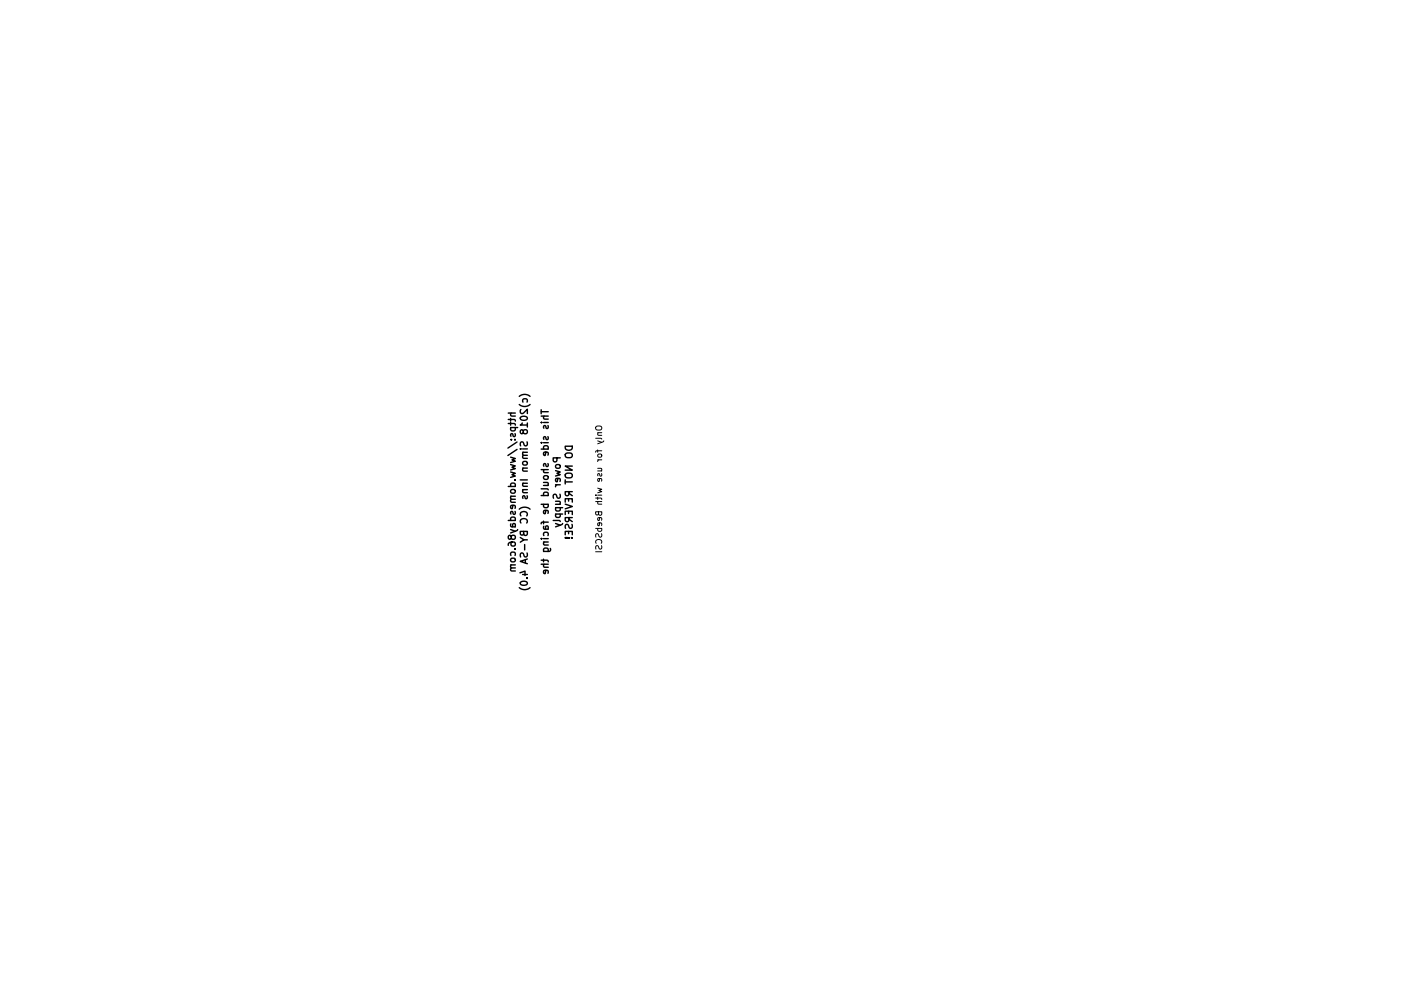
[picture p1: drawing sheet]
<svg xmlns="http://www.w3.org/2000/svg" width="297mm" height="210mm" viewBox="0 0 297 210" stroke-linecap="round" stroke-linejoin="round" font-family="sans-serif">
<g fill="none" stroke="#000" stroke-width=".21">
<path d="M126.3 93h1.1l.2 .2M126.5 90.4h.7a.43 .43 0 0 1 .4 .4 .43 .43 0 0 1-.4 .4h-.5a.44 .44 0 0 1-.4-.3 .44 .44 0 0 1 .2-.5zM126.7 99.4h.8v.5M126.7 91.8h.9M126.7 93.5l.9 .3M126.7 95.5v.5M126.7 97.6h.9M126.7 99.9h.9M126.8 96.4l.5-.1 .3 .5-.3 .2h-.3l-.3-.2zM126.8 91.8v.5l.8 .1M127 97.6l-.3 .3M127.6 95.6h-1.1l-.2 .4"/>
<path d="M128 93.5l-.1 .2-1.2 .5M126.3 105.1h.1M126.3 105.7h1.1l.2 .3M126.3 106.4h1.3M126.3 112.1h1.3M126.3 117.1h1.3M126.4 115.3a.58 .58 0 0 1 .5-.8 .58 .58 0 0 1 .6 .8M126.7 103.6l.9 .2-.6 .3 .6 .2-.9 .3M126.7 105.5v.5M126.7 105.1h.9M126.8 112.1l-.1 .4 .3 .2 .5-.1v-.5M126.8 106.4v.5l.8 .1"/>
<path d="M126.9 108.6l-.1 .5-.4 .1-.1-.6h1.3v.5l-.4 .2-.3-.3M127.2 101.5l-.2 .6h-.2l-.1-.4 .2-.2 .6 .1v.5M127.2 109.8l-.2 .6h-.2l-.1-.4 .2-.2 .6 .1v.5M127.2 110.9l-.2 .7-.2-.1-.1-.4 .2-.2 .6 .1v.5M127.5 100.5v.5h-.3l-.2-.5-.3 .2 .1 .3M127.5 113.2l.1 .5-.1 .2h-.4l-.3-.6-.3-.1-.2 .3 .1 .5M127.5 115.8l.1 .5-.3 .2-.3-.1-.2-.6h-.4l-.1 .2 .1 .5"/>
</g>
<g fill="none" stroke="#000" stroke-width=".3">
<path d="M107.8 89h1.2l.3 .4M107.8 89.9h1.2l.3 .3M107.8 87.6h1.5M108.3 97l1 .3-.8 .3 .8 .3-1 .2M108.3 98.6l1 .3-.8 .2 .8 .3-1 .3M108.3 88.8v.6M108.3 89.6v.6M108.3 90.7h1.5M108.3 90.7v.4l.2 .3 .7-.1v-.6M108.3 93.3h.2M108.4 87.6l-.1 .3v.3l1 .1M109.1 93.3h.2"/>
<path d="M109.2 92v.6h-.4l-.3-.6-.2 .2v.4M109.6 93.8l-1.9 1.3M109.6 95.4l-1.9 1.2M110.1 84.1a1.72 1.72 0 0 1 2.3 0M110.1 85.8a1.72 1.72 0 0 0 2.3 0M110.3 95.2h.2M110.4 88.5a.89 .89 0 0 1 1.4 .3 .85 .85 0 0 1-1.5-.1zM110.5 86.9l-.2 .6 .4 .2 1.1-.9v.9M110.7 89.7l-.4 .5h1.5M110.8 95.2h1M110.8 96h1M110.8 99.3h1"/>
<path d="M110.9 85.3l-.1-.4 .3-.3 .6 .1v.6M110.9 98l.6-.1 .2 .1 .1 .4-.3 .3h-.4l-.3-.3zM111 91.5l-.3-.3h-.2l-.2 .3 .1 .4 .4 .1 .2-.7 .2-.1h.5l.1 .3v.2l-.3 .3h-.4l-.1-.3M111 96l-.2 .2 .1 .3 .9 .1M111 99.3l-.2 .2 .1 .4 .9 .1M111 96.6l-.2 .2 .1 .4h.9M111.7 93.7l.1 .6-.3 .3-.3-.1-.3-.7h-.4l-.2 .2 .1 .6M111.8 89.7v.9M114.7 89.6h.2M114.7 93.9h.2M114.7 86.9v.9M114.7 87.4h1.5"/>
<path d="M114.7 88.3h1.5M114.7 95.3h1.5M114.7 99.6h1.5M115.2 89.6h1M115.2 93.9h1M115.3 95.3l-.1-.4 .3-.3 .7 .1v.6M115.4 88.3l-.2 .2 .1 .4h.9M115.4 99.6l-.2 .3 .1 .3 .9 .1M115.7 95.9l-.1 .7h-.3l-.1-.5 .3-.2 .7 .1v.6M116.2 90.3v.6h-.4l-.3-.6-.3 .2 .1 .4M116.2 92.6v.6h-.4l-.3-.6-.3 .3 .1 .3M116.2 98.4v.5h-.4l-.3-.5-.3 .2 .1 .3"/>
<path d="M117.8 99.9l1 .2-.7 .3 .7 .3-1 .3M117.9 98.6h.7l.2 .3-.1 .3-.2 .2-.6-.1-.1-.2zM118.1 97.1l-.1 .8-.2 .1-.4-.1-.1-.8h1.5M119.8 94.7h1.5a.76 .76 0 0 1-.7 .8 .76 .76 0 0 1-.8-.8zM120.1 96.2a1.01 1.01 0 0 1 1.2 .3 .5 .5 0 0 1-.5 .6h-.5a.5 .5 0 0 1-.5-.4 .5 .5 0 0 1 .3-.5zM121.3 98.9h-1.5l1.5 .8h-1.5M107.8 103.2h1.5M107.8 110.4h1.5M108.3 100.1l1 .3-.8 .3 .8 .3-1 .3M108.3 105.3h1M108.3 112.4l1 .3M108.3 119.9h1"/>
<path d="M108.3 103.2v-.4l.2-.3 .7 .1v.6M108.3 110.4v-.4l.2-.3 .7 .2v.5M108.3 111.1v.6l1 .1M108.3 117.9v-.5l.2-.3 .7 .2v.6M108.4 103.9h.7l.2 .2-.1 .4-.2 .1h-.6l-.1-.2zM108.4 105.3l-.1 .2v.4h1M108.4 113.9l-.3-.3h-.2l-.1 .3v.4l.5 .1 .2-.7 .2-.1h.4l.2 .3-.1 .4-.2 .1h-.3l-.3-.3M108.4 118.5h.7l.2 .2-.1 .4-.2 .1-.6-.1-.1-.2zM108.4 119.9l-.1 .2v.3l1 .1M108.5 105.9l-.2 .2v.4l1 .1M108.6 111.8l.1-.5 .2-.2 .4 .2-.1 .5M108.6 115l-.3 .3 .1 .4 .2 .2h.4l.3-.3-.1-.5-.2-.1a1 1 0 0 0-1.2 .4v.3"/>
<path d="M108.8 107.2l-.2 .7h-.3v-.5l.2-.2 .7 .1v.6M109.1 101.9h.2M109.1 116.5h.2M109.2 108.5v.6h-.4l-.3-.6-.2 .2v.4M109.8 112.4l-.2 .2-1.3 .5M110.1 108a1.72 1.72 0 0 1 2.3 0M110.3 114l.8 .5-.8 .5M110.3 101.8h1.5M110.5 109.5a.71 .71 0 0 1 .5-1 .71 .71 0 0 1 .8 .7l-.1 .3M110.5 111a.71 .71 0 0 1 .5-1 .71 .71 0 0 1 .8 .7l-.1 .3M110.8 102.5h1M110.8 103.9h1"/>
<path d="M111 102.5l-.2 .2 .1 .4 .9 .1M111 103.9l-.2 .2 .1 .4h.9M111 112.7v.7l-.3 .1h-.2l-.2-.8h1.5v.6l-.1 .2-.4 .1-.3-.4M111.1 114.5h.7M111.2 115.5v1.2M111.4 118.7v.8M111.7 105.2v.5h-.3l-.3-.5-.3 .2 .1 .3M111.7 117.3l.1 .6-.1 .2h-.5l-.2-.6-.4-.2-.3 .3 .1 .6M111.8 118.6l-1.5 .5 1.5 .5M114.7 103.7h1.3l.2 .2M114.7 114.3h.2M114.7 118.9h1.3l.2 .3"/>
<path d="M114.7 105.1h1.5M114.7 107h1.5M114.7 119.7h1.5M115.2 102.4h1v.4l-.1 .2M115.2 103h1M115.2 110.6v.5M115.2 118.6v.6M115.2 114.3h1M115.2 115h1M115.3 101.1l.7-.2 .2 .2v.3l-.2 .3h-.5l-.3-.3zM115.3 105.1l-.1-.4 .3-.3 .7 .2v.5M115.3 107l-.1 .4 .3 .3 .7-.1v-.6"/>
<path d="M115.3 111.6v.6l.9 .1M115.3 113.6l-.1-.4 .3-.3 .7 .2v.5M115.3 117l-.1-.4 .3-.3 .7 .1v.6M115.4 115l-.2 .2 .1 .4h.9M115.4 119.7l-.2 .2 .1 .4 .9 .1M115.6 112.3l.1-.5 .2-.2 .3 .2v.5M115.7 108.3l-.1 .7-.3-.1-.1-.4 .3-.2 .7 .1v.5M116.2 110.8h-1.2l-.3 .3M116.7 116.4v.3l-.2 .3h-1.3M117.3 110.4h1.3l.2 .2M117.8 106.4h.9l.1 .4-.2 .2M117.8 107h1"/>
<path d="M117.8 102.9h1M117.8 107.7h1.5M117.8 109.1h1.5M117.8 111.1l1 .3M117.9 107.7l-.1 .4 .3 .3 .6-.1v-.6M117.9 109.1l-.1 .4 .3 .3 .6-.2v-.5M118.1 102.9l-.3 .4M118.3 101.5l-.2 .7-.2-.1-.1-.4 .2-.2 .7 .1v.5M118.7 104.9l.1 .5-.2 .2h-.4l-.3-.6-.3-.1-.3 .2 .1 .6M119.3 111.1l-.2 .2-1.3 .5M119.8 106.5v-.7h1.5v.7M119.8 107l1.5 .5-1.5 .5"/>
<path d="M119.8 109.2v-.7h1.5v.7M119.8 113.5v-.8h1.5v.8M119.8 114.1h1M119.8 101.8v.9M119.8 102.2h1.5M120.1 100.5a1.01 1.01 0 0 1 1.2 .2 .5 .5 0 0 1-.5 .7h-.5a.5 .5 0 0 1-.5-.4 .5 .5 0 0 1 .3-.5zM120.6 105.8v.5M120.6 108.5v.5M120.6 112.7v.5M120.6 104.3v.7l-.3 .2-.3-.1-.2-.8h1.5M120.6 109.8v.7l-.3 .2-.3-.1-.2-.8h1.5M120.6 104.7l.7 .5"/>
<path d="M120.6 110.2l.7 .5M121.2 114.1h.1M121.3 111.2v.6l-.2 .3-.4-.1-.3-.7h-.4l-.2 .2 .1 .6M108.5 120.5l-.2 .2v.4h1M110.1 124.7a1.72 1.72 0 0 0 2.3 0M110.2 121.5l1.1-.3v.9M110.5 123.5a.81 .81 0 0 1 1.3 .3 .85 .85 0 0 1-1.5-.1zM110.8 121.9h1M111.7 122.7h.1M115.7 121l-.1 .7-.3-.1-.1-.4 .3-.2 .7 .1v.5"/>
</g>
</svg>
